VERSION 5.8 ;
BUSBITCHARS "[]" ;
DIVIDERCHAR "/" ;
UNITS
    DATABASE MICRONS 1000 ;
END UNITS

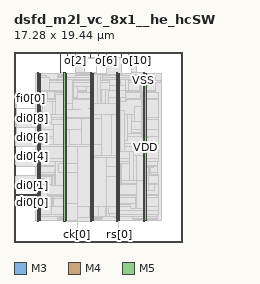
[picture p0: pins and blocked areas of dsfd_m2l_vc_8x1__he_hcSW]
MACRO dsfd_m2l_vc_8x1__he_hcSW
  FOREIGN dsfd_m2l_vc_8x1__he_hcSW 0 0 ;
  CLASS BLOCK ;
  SIZE 17.28 BY 19.44 ;
  PIN ck[0]
    DIRECTION INPUT ;
    USE SIGNAL ;
    PORT
      LAYER M3 ;
        RECT  6.48 0 6.498 0.144 ;
    END
    PORT
      LAYER M3 ;
        RECT  6.48 0.108 6.498 0.173 ;
    END
  END ck[0]
  PIN di0[0]
    DIRECTION INPUT ;
    USE SIGNAL ;
    PORT
      LAYER M4 ;
        RECT  0 4.8 0.192 4.824 ;
    END
    PORT
      LAYER M4 ;
        RECT  0.156 4.8 2.408 4.824 ;
    END
  END di0[0]
  PIN di0[1]
    DIRECTION INPUT ;
    USE SIGNAL ;
    PORT
      LAYER M4 ;
        RECT  0 5.808 0.192 5.832 ;
    END
  END di0[1]
  PIN di0[2]
    DIRECTION INPUT ;
    USE SIGNAL ;
    PORT
      LAYER M4 ;
        RECT  0 6.768 0.192 6.792 ;
    END
  END di0[2]
  PIN di0[3]
    DIRECTION INPUT ;
    USE SIGNAL ;
    PORT
      LAYER M4 ;
        RECT  0 7.776 0.192 7.8 ;
    END
  END di0[3]
  PIN di0[4]
    DIRECTION INPUT ;
    USE SIGNAL ;
    PORT
      LAYER M4 ;
        RECT  0 8.736 0.192 8.76 ;
    END
  END di0[4]
  PIN di0[5]
    DIRECTION INPUT ;
    USE SIGNAL ;
    PORT
      LAYER M4 ;
        RECT  0 9.744 0.192 9.768 ;
    END
  END di0[5]
  PIN di0[6]
    DIRECTION INPUT ;
    USE SIGNAL ;
    PORT
      LAYER M4 ;
        RECT  0 10.704 0.192 10.728 ;
    END
  END di0[6]
  PIN di0[7]
    DIRECTION INPUT ;
    USE SIGNAL ;
    PORT
      LAYER M4 ;
        RECT  0 11.712 0.192 11.736 ;
    END
  END di0[7]
  PIN di0[8]
    DIRECTION INPUT ;
    USE SIGNAL ;
    PORT
      LAYER M4 ;
        RECT  0 12.672 0.192 12.696 ;
    END
  END di0[8]
  PIN di0[9]
    DIRECTION INPUT ;
    USE SIGNAL ;
    PORT
      LAYER M4 ;
        RECT  0 13.68 0.192 13.704 ;
    END
  END di0[9]
  PIN fi0[0]
    DIRECTION INPUT ;
    USE SIGNAL ;
    PORT
      LAYER M4 ;
        RECT  0 14.64 0.192 14.664 ;
    END
  END fi0[0]
  PIN o[0]
    DIRECTION OUTPUT ;
    USE SIGNAL ;
    PORT
      LAYER M3 ;
        RECT  4.716 19.296 4.734 19.44 ;
    END
    PORT
      LAYER M3 ;
        RECT  4.716 17.297 4.734 19.308 ;
    END
  END o[0]
  PIN o[10]
    DIRECTION OUTPUT ;
    USE SIGNAL ;
    PORT
      LAYER M3 ;
        RECT  12.564 19.296 12.582 19.44 ;
    END
    PORT
      LAYER M3 ;
        RECT  12.564 18.845 12.582 19.308 ;
    END
  END o[10]
  PIN o[1]
    DIRECTION OUTPUT ;
    USE SIGNAL ;
    PORT
      LAYER M5 ;
        RECT  5.472 19.248 5.496 19.44 ;
    END
    PORT
      LAYER M5 ;
        RECT  5.472 18.805 5.496 19.28 ;
    END
  END o[1]
  PIN o[2]
    DIRECTION OUTPUT ;
    USE SIGNAL ;
    PORT
      LAYER M3 ;
        RECT  6.264 19.296 6.282 19.44 ;
    END
    PORT
      LAYER M3 ;
        RECT  6.264 18.845 6.282 19.308 ;
    END
  END o[2]
  PIN o[3]
    DIRECTION OUTPUT ;
    USE SIGNAL ;
    PORT
      LAYER M5 ;
        RECT  7.056 19.248 7.08 19.44 ;
    END
    PORT
      LAYER M5 ;
        RECT  7.056 18.805 7.08 19.28 ;
    END
  END o[3]
  PIN o[4]
    DIRECTION OUTPUT ;
    USE SIGNAL ;
    PORT
      LAYER M3 ;
        RECT  7.848 19.296 7.866 19.44 ;
    END
    PORT
      LAYER M3 ;
        RECT  7.848 18.845 7.866 19.308 ;
    END
  END o[4]
  PIN o[5]
    DIRECTION OUTPUT ;
    USE SIGNAL ;
    PORT
      LAYER M5 ;
        RECT  8.64 19.248 8.664 19.44 ;
    END
    PORT
      LAYER M5 ;
        RECT  8.64 18.805 8.664 19.28 ;
    END
  END o[5]
  PIN o[6]
    DIRECTION OUTPUT ;
    USE SIGNAL ;
    PORT
      LAYER M3 ;
        RECT  9.432 19.296 9.45 19.44 ;
    END
    PORT
      LAYER M3 ;
        RECT  9.432 18.914 9.45 19.308 ;
    END
  END o[6]
  PIN o[7]
    DIRECTION OUTPUT ;
    USE SIGNAL ;
    PORT
      LAYER M5 ;
        RECT  10.176 19.248 10.2 19.44 ;
    END
    PORT
      LAYER M5 ;
        RECT  10.176 18.805 10.2 19.28 ;
    END
  END o[7]
  PIN o[8]
    DIRECTION OUTPUT ;
    USE SIGNAL ;
    PORT
      LAYER M3 ;
        RECT  10.98 19.296 10.998 19.44 ;
    END
    PORT
      LAYER M3 ;
        RECT  10.98 18.845 10.998 19.308 ;
    END
  END o[8]
  PIN o[9]
    DIRECTION OUTPUT ;
    USE SIGNAL ;
    PORT
      LAYER M5 ;
        RECT  11.76 19.248 11.784 19.44 ;
    END
    PORT
      LAYER M5 ;
        RECT  11.76 18.805 11.784 19.28 ;
    END
  END o[9]
  PIN rs[0]
    DIRECTION INPUT ;
    USE SIGNAL ;
    PORT
      LAYER M5 ;
        RECT  10.8 0 10.824 0.192 ;
    END
    PORT
      LAYER M5 ;
        RECT  10.8 0.144 10.824 0.227 ;
    END
  END rs[0]
  PIN VDD
    DIRECTION INOUT ;
    USE POWER ;
    PORT
      LAYER M5 ;
        RECT  13.392 2.151 13.512 17.289 ;
        RECT  10.692 2.151 10.812 17.289 ;
        RECT  7.992 2.151 8.112 17.289 ;
        RECT  5.292 2.151 5.412 17.289 ;
        RECT  2.592 2.151 2.712 17.289 ;
    END
  END VDD
  PIN VSS
    DIRECTION INOUT ;
    USE GROUND ;
    PORT
      LAYER M5 ;
        RECT  13.2 2.137 13.32 17.303 ;
        RECT  10.5 2.137 10.62 17.303 ;
        RECT  7.8 2.137 7.92 17.303 ;
        RECT  5.1 2.137 5.22 17.303 ;
        RECT  2.4 2.137 2.52 17.303 ;
    END
  END VSS
  # OT_OBS_CLOSED layer=M5 d_um=1.536 added=14
  OBS
    LAYER RVTN ;
     RECT  2.16 2.16 15.12 2.295 ;
     RECT  2.16 2.565 15.12 2.835 ;
     RECT  2.16 3.105 15.12 3.375 ;
     RECT  2.16 3.645 15.12 3.915 ;
     RECT  2.16 4.185 15.12 4.455 ;
     RECT  2.16 4.725 15.12 4.995 ;
     RECT  2.16 5.265 15.12 5.535 ;
     RECT  2.16 5.805 15.12 6.075 ;
     RECT  2.16 6.345 15.12 6.615 ;
     RECT  2.16 6.885 15.12 7.155 ;
     RECT  2.16 7.425 15.12 7.695 ;
     RECT  2.16 7.965 15.12 8.235 ;
     RECT  2.16 8.505 15.12 8.775 ;
     RECT  2.16 9.045 15.12 9.315 ;
     RECT  2.16 9.585 15.12 9.855 ;
     RECT  2.16 10.125 15.12 10.395 ;
     RECT  2.16 10.665 15.12 10.935 ;
     RECT  2.16 11.205 15.12 11.475 ;
     RECT  2.16 11.745 15.12 12.015 ;
     RECT  2.16 12.285 15.12 12.555 ;
     RECT  2.16 12.825 15.12 13.095 ;
     RECT  2.16 13.365 15.12 13.635 ;
     RECT  2.16 13.905 15.12 14.175 ;
     RECT  2.16 14.445 15.12 14.715 ;
     RECT  2.16 14.985 15.12 15.255 ;
     RECT  2.16 15.525 15.12 15.795 ;
     RECT  2.16 16.065 15.12 16.335 ;
     RECT  2.16 16.605 15.12 16.875 ;
     RECT  2.16 17.145 15.12 17.28 ;
    LAYER RVTP ;
     RECT  2.16 2.295 15.12 2.565 ;
     RECT  2.16 2.835 15.12 3.105 ;
     RECT  2.16 3.375 15.12 3.645 ;
     RECT  2.16 3.915 15.12 4.185 ;
     RECT  2.16 4.455 15.12 4.725 ;
     RECT  2.16 4.995 15.12 5.265 ;
     RECT  2.16 5.535 15.12 5.805 ;
     RECT  2.16 6.075 15.12 6.345 ;
     RECT  2.16 6.615 15.12 6.885 ;
     RECT  2.16 7.155 15.12 7.425 ;
     RECT  2.16 7.695 15.12 7.965 ;
     RECT  2.16 8.235 15.12 8.505 ;
     RECT  2.16 8.775 15.12 9.045 ;
     RECT  2.16 9.315 15.12 9.585 ;
     RECT  2.16 9.855 15.12 10.125 ;
     RECT  2.16 10.395 15.12 10.665 ;
     RECT  2.16 10.935 15.12 11.205 ;
     RECT  2.16 11.475 15.12 11.745 ;
     RECT  2.16 12.015 15.12 12.285 ;
     RECT  2.16 12.555 15.12 12.825 ;
     RECT  2.16 13.095 15.12 13.365 ;
     RECT  2.16 13.635 15.12 13.905 ;
     RECT  2.16 14.175 15.12 14.445 ;
     RECT  2.16 14.715 15.12 14.985 ;
     RECT  2.16 15.255 15.12 15.525 ;
     RECT  2.16 15.795 15.12 16.065 ;
     RECT  2.16 16.335 15.12 16.605 ;
     RECT  2.16 16.875 15.12 17.145 ;
    LAYER M1 ;
     RECT  2.16 2.151 15.12 17.289 ;
    LAYER M2 ;
     RECT  7.843 18.81 8.447 18.828 ;
     RECT  9.427 18.891 10.067 18.909 ;
     RECT  2.16 2.151 15.12 17.289 ;
    LAYER M3 ;
     RECT  10.656 0.187 10.674 2.143 ;
     RECT  13.215 2.143 13.305 2.191 ;
     RECT  12.456 2.191 13.305 2.227 ;
     RECT  5.115 2.143 5.205 2.263 ;
     RECT  12.456 2.227 13.698 2.263 ;
     RECT  14.616 2.191 14.634 2.263 ;
     RECT  7.815 2.143 7.905 2.299 ;
     RECT  4.716 2.263 5.205 2.335 ;
     RECT  6.588 2.293 6.606 2.335 ;
     RECT  7.815 2.299 8.73 2.335 ;
     RECT  4.5 2.335 5.67 2.371 ;
     RECT  6.48 2.335 8.982 2.371 ;
     RECT  12.24 2.263 14.634 2.371 ;
     RECT  2.415 2.143 2.505 2.413 ;
     RECT  10.515 2.143 10.674 2.413 ;
     RECT  10.515 2.413 10.797 2.497 ;
     RECT  4.5 2.371 9.054 2.533 ;
     RECT  4.464 2.533 9.054 2.569 ;
     RECT  10.224 2.497 10.797 2.569 ;
     RECT  4.392 2.569 9.378 2.605 ;
     RECT  2.415 2.413 2.697 2.641 ;
     RECT  4.032 2.605 9.378 2.641 ;
     RECT  10.224 2.569 11.106 2.641 ;
     RECT  12.132 2.371 14.634 2.641 ;
     RECT  2.415 2.641 14.634 2.767 ;
     RECT  2.415 2.767 14.778 3.181 ;
     RECT  2.376 3.181 14.778 3.629 ;
     RECT  2.415 3.629 14.778 4.523 ;
     RECT  2.415 4.523 14.742 4.765 ;
     RECT  2.304 4.765 14.742 4.829 ;
     RECT  2.415 4.829 14.742 5.851 ;
     RECT  2.376 5.851 14.742 5.999 ;
     RECT  2.415 5.999 14.742 6.763 ;
     RECT  2.412 6.763 14.742 6.881 ;
     RECT  2.412 6.881 14.67 7.087 ;
     RECT  2.376 7.087 14.67 7.735 ;
     RECT  2.304 7.735 14.67 7.805 ;
     RECT  2.376 7.805 14.67 8.239 ;
     RECT  2.376 8.239 14.814 8.573 ;
     RECT  2.415 8.573 14.814 9.739 ;
     RECT  2.304 9.739 14.814 10.085 ;
     RECT  2.376 10.085 14.814 10.769 ;
     RECT  2.415 10.769 14.814 11.471 ;
     RECT  2.415 11.471 14.778 12.487 ;
     RECT  2.304 12.487 14.778 12.701 ;
     RECT  2.415 12.701 14.778 14.611 ;
     RECT  2.415 14.611 14.814 14.639 ;
     RECT  2.415 14.639 3.402 14.647 ;
     RECT  4.176 14.639 14.814 15.251 ;
     RECT  2.376 14.647 3.402 15.421 ;
     RECT  4.176 15.251 14.526 15.421 ;
     RECT  2.376 15.421 14.526 15.485 ;
     RECT  2.415 15.485 14.526 16.339 ;
     RECT  2.415 16.339 14.994 16.529 ;
     RECT  2.415 16.529 14.526 16.601 ;
     RECT  2.415 16.601 13.77 16.673 ;
     RECT  2.415 16.673 3.582 16.795 ;
     RECT  2.376 16.795 3.582 16.835 ;
     RECT  4.5 16.673 13.77 16.835 ;
     RECT  14.508 16.601 14.526 16.835 ;
     RECT  4.5 16.835 5.49 16.979 ;
     RECT  2.376 16.835 3.33 17.027 ;
     RECT  4.5 16.979 5.397 17.027 ;
     RECT  2.376 17.027 2.538 17.069 ;
     RECT  3.312 17.027 3.33 17.069 ;
     RECT  6.264 16.835 13.77 17.069 ;
     RECT  4.5 17.027 5.205 17.105 ;
     RECT  11.988 17.069 13.305 17.105 ;
     RECT  6.264 17.069 11.106 17.117 ;
     RECT  9.324 17.117 11.106 17.177 ;
     RECT  6.264 17.117 8.514 17.213 ;
     RECT  2.415 17.069 2.505 17.297 ;
     RECT  4.716 17.105 5.205 17.297 ;
     RECT  6.264 17.213 8.442 17.297 ;
     RECT  12.06 17.105 13.305 17.297 ;
     RECT  6.264 17.297 7.182 18.805 ;
     RECT  8.424 17.297 8.442 18.805 ;
     RECT  6.264 18.805 8.442 18.833 ;
     RECT  6.264 18.833 7.866 18.845 ;
     RECT  9.432 17.177 10.998 18.845 ;
     RECT  12.06 17.297 12.582 18.845 ;
     RECT  9.432 18.845 10.062 18.914 ;
    LAYER M4 ;
     RECT  0.156 13.68 0.275 14.664 ;
     RECT  2.365 3.6 2.408 3.624 ;
     RECT  0.156 5.808 2.408 6.792 ;
     RECT  0.156 7.776 2.408 8.76 ;
     RECT  0.156 9.744 2.408 10.728 ;
     RECT  0.156 11.712 2.408 12.696 ;
     RECT  0.275 13.68 2.408 13.704 ;
     RECT  2.365 15.456 2.408 15.48 ;
     RECT  2.365 16.8 2.408 16.824 ;
     RECT  2.408 2.148 2.512 17.292 ;
     RECT  2.512 2.418 2.704 17.022 ;
     RECT  2.704 9.936 2.819 14.376 ;
     RECT  2.819 12.24 2.917 14.376 ;
     RECT  2.704 15.456 3.593 16.824 ;
     RECT  2.704 3.312 3.805 4.68 ;
     RECT  2.917 12.24 3.805 13.08 ;
     RECT  2.704 5.856 3.841 6.696 ;
     RECT  3.805 12 3.845 13.08 ;
     RECT  3.805 2.832 3.889 4.68 ;
     RECT  3.841 5.808 3.913 6.696 ;
     RECT  3.845 13.056 3.949 13.08 ;
     RECT  2.917 14.352 3.949 14.376 ;
     RECT  2.819 9.936 4.021 10.632 ;
     RECT  3.845 12 4.021 12.024 ;
     RECT  3.889 3.312 4.061 4.68 ;
     RECT  2.704 8.544 4.061 8.568 ;
     RECT  3.913 5.808 4.165 6.84 ;
     RECT  3.949 13.056 4.237 14.376 ;
     RECT  4.165 5.808 4.273 7.464 ;
     RECT  4.061 3.312 5.108 3.336 ;
     RECT  4.061 4.464 5.108 4.68 ;
     RECT  4.273 5.808 5.108 8.232 ;
     RECT  4.021 9.936 5.108 12.024 ;
     RECT  4.237 13.056 5.108 15.048 ;
     RECT  5.108 2.148 5.212 17.292 ;
     RECT  5.212 2.418 5.404 17.022 ;
     RECT  5.404 13.584 6.035 16.632 ;
     RECT  6.035 14.832 6.049 16.632 ;
     RECT  5.404 3.984 6.275 8.808 ;
     RECT  6.275 3.984 6.316 5.832 ;
     RECT  6.275 6.816 6.469 8.808 ;
     RECT  5.404 10.176 6.469 12.312 ;
     RECT  6.049 14.832 6.473 15.864 ;
     RECT  6.428 0.144 6.515 0.168 ;
     RECT  5.404 2.544 6.577 2.568 ;
     RECT  6.469 6.816 6.581 12.312 ;
     RECT  6.577 2.304 6.649 2.568 ;
     RECT  6.316 3.984 6.649 4.584 ;
     RECT  6.035 13.584 6.761 13.608 ;
     RECT  6.581 7.2 6.829 12.312 ;
     RECT  5.461 18.816 7.193 18.84 ;
     RECT  6.316 5.76 7.261 5.832 ;
     RECT  6.649 2.304 7.369 4.584 ;
     RECT  7.261 5.76 7.369 6.216 ;
     RECT  6.473 15.504 7.441 15.864 ;
     RECT  7.369 2.304 7.808 6.216 ;
     RECT  6.829 7.2 7.808 12.648 ;
     RECT  7.657 13.632 7.808 13.656 ;
     RECT  7.441 15.312 7.808 15.864 ;
     RECT  7.477 17.088 7.808 17.112 ;
     RECT  7.808 2.148 7.912 17.292 ;
     RECT  7.912 2.304 8.021 17.112 ;
     RECT  8.021 2.418 8.104 17.112 ;
     RECT  8.104 8.544 8.561 17.112 ;
     RECT  8.104 2.64 8.669 7.368 ;
     RECT  8.561 9.792 8.849 17.112 ;
     RECT  8.849 9.792 8.963 15.576 ;
     RECT  8.849 16.56 9.065 17.112 ;
     RECT  8.963 11.232 9.317 15.576 ;
     RECT  8.669 2.64 9.349 7.32 ;
     RECT  9.317 12.576 9.353 15.576 ;
     RECT  8.561 8.544 9.421 8.808 ;
     RECT  9.349 2.592 9.461 7.32 ;
     RECT  9.421 8.448 9.884 8.808 ;
     RECT  8.963 9.792 9.884 10.2 ;
     RECT  9.065 16.56 10.141 16.584 ;
     RECT  9.884 8.448 10.249 10.2 ;
     RECT  9.317 11.232 10.249 11.4 ;
     RECT  9.461 5.232 10.309 7.32 ;
     RECT  10.249 8.448 10.309 11.4 ;
     RECT  10.141 16.56 10.309 16.632 ;
     RECT  9.353 12.768 10.429 15.576 ;
     RECT  10.309 16.56 10.429 16.824 ;
     RECT  8.629 18.816 10.469 18.84 ;
     RECT  9.461 2.592 10.508 4.248 ;
     RECT  10.309 5.232 10.508 11.4 ;
     RECT  10.429 12.768 10.508 16.824 ;
     RECT  10.508 2.148 10.612 17.292 ;
     RECT  10.612 2.418 10.804 17.022 ;
     RECT  10.645 0.192 10.835 0.216 ;
     RECT  10.804 9.216 10.901 16.632 ;
     RECT  10.804 5.76 10.937 7.992 ;
     RECT  10.937 6 11.009 7.992 ;
     RECT  10.901 9.216 11.333 13.416 ;
     RECT  10.901 14.4 11.459 16.632 ;
     RECT  11.459 14.4 11.513 14.472 ;
     RECT  11.333 10.368 11.657 13.08 ;
     RECT  11.459 15.456 11.729 16.632 ;
     RECT  11.009 6.288 11.833 7.992 ;
     RECT  11.333 9.216 11.833 9.24 ;
     RECT  10.804 3.888 11.941 3.96 ;
     RECT  11.657 11.136 12.053 13.08 ;
     RECT  11.749 18.816 12.089 18.84 ;
     RECT  11.833 6.288 12.197 9.24 ;
     RECT  12.053 12.288 12.301 13.08 ;
     RECT  11.941 3.408 12.476 3.96 ;
     RECT  12.197 6.288 12.517 8.856 ;
     RECT  11.729 15.456 12.841 15.48 ;
     RECT  11.729 16.56 12.841 16.632 ;
     RECT  12.841 15.456 12.913 16.632 ;
     RECT  12.913 14.928 12.985 16.632 ;
     RECT  12.053 11.136 13.052 11.16 ;
     RECT  12.301 12.288 13.052 13.848 ;
     RECT  13.052 11.136 13.093 13.848 ;
     RECT  12.985 14.832 13.093 16.632 ;
     RECT  12.517 2.208 13.208 2.232 ;
     RECT  12.476 3.408 13.208 4.536 ;
     RECT  12.517 5.616 13.208 8.856 ;
     RECT  13.093 10.704 13.208 16.632 ;
     RECT  13.208 2.148 13.312 17.292 ;
     RECT  13.312 2.418 13.504 17.022 ;
     RECT  13.504 3.696 13.565 3.72 ;
     RECT  13.504 10.704 13.742 10.728 ;
     RECT  13.504 5.28 13.745 7.656 ;
     RECT  13.504 9.216 13.781 9.24 ;
     RECT  13.745 6.864 13.907 7.656 ;
     RECT  13.907 7.008 13.961 7.656 ;
     RECT  13.504 16.032 14.069 16.056 ;
     RECT  13.961 7.632 14.285 7.656 ;
     RECT  13.745 5.28 14.357 5.88 ;
     RECT  14.357 5.856 14.465 5.88 ;
     RECT  13.504 14.688 14.753 14.712 ;
    LAYER M5 ;
     RECT  2.4 2.137 2.52 2.151 ;
     RECT  5.1 2.137 5.22 2.151 ;
     RECT  7.8 2.137 7.92 2.151 ;
     RECT  10.5 2.137 10.62 2.151 ;
     RECT  13.2 2.137 13.32 2.151 ;
     RECT  7.8 2.151 8.112 2.533 ;
     RECT  10.5 2.151 10.812 2.581 ;
     RECT  9.792 2.581 10.812 2.869 ;
     RECT  13.2 2.151 13.512 3.397 ;
     RECT  2.4 2.151 2.712 3.589 ;
     RECT  3.84 2.821 3.864 3.589 ;
     RECT  9.696 2.869 10.812 3.589 ;
     RECT  2.4 3.589 3.864 3.635 ;
     RECT  7.68 2.533 8.112 3.635 ;
     RECT  5.1 2.151 5.412 3.973 ;
     RECT  6.48 0.133 6.504 3.973 ;
     RECT  2.4 3.635 2.952 4.645 ;
     RECT  2.4 4.645 3.432 5.891 ;
     RECT  12.528 3.397 13.512 6.323 ;
     RECT  2.4 5.891 3.24 6.515 ;
     RECT  9.456 3.589 10.812 6.661 ;
     RECT  13.2 6.323 13.512 6.853 ;
     RECT  13.2 6.853 13.896 7.043 ;
     RECT  5.1 3.973 6.504 7.093 ;
     RECT  9.456 6.661 10.92 7.763 ;
     RECT  4.56 7.093 6.504 8.003 ;
     RECT  7.8 3.635 8.112 8.677 ;
     RECT  9.456 7.763 10.812 8.677 ;
     RECT  7.8 8.677 10.812 8.819 ;
     RECT  5.1 8.003 6.504 9.731 ;
     RECT  7.8 8.819 8.952 9.925 ;
     RECT  13.2 7.043 13.512 10.693 ;
     RECT  2.4 6.515 2.712 11.365 ;
     RECT  5.1 9.731 5.688 11.555 ;
     RECT  2.4 11.365 2.808 12.275 ;
     RECT  6.912 9.925 8.952 12.611 ;
     RECT  7.008 12.611 8.952 12.659 ;
     RECT  7.8 12.659 8.952 13.045 ;
     RECT  9.936 8.819 10.812 13.045 ;
     RECT  2.4 12.275 2.712 13.429 ;
     RECT  7.8 13.045 10.812 14.147 ;
     RECT  5.1 11.555 5.412 14.197 ;
     RECT  2.4 13.429 2.904 14.387 ;
     RECT  0.24 10.357 0.264 14.675 ;
     RECT  9.696 14.147 10.812 14.773 ;
     RECT  13.104 10.693 13.512 15.443 ;
     RECT  9.696 14.773 11.448 15.491 ;
     RECT  9.744 15.491 11.448 16.019 ;
     RECT  9.744 16.019 10.812 16.595 ;
     RECT  5.1 14.197 6.024 16.643 ;
     RECT  10.32 16.595 10.812 16.835 ;
     RECT  2.4 14.387 2.712 17.289 ;
     RECT  5.1 16.643 5.412 17.289 ;
     RECT  7.8 14.147 8.112 17.289 ;
     RECT  10.5 16.835 10.812 17.289 ;
     RECT  13.2 15.443 13.512 17.289 ;
     RECT  2.4 17.289 2.52 17.303 ;
     RECT  5.1 17.289 5.22 17.303 ;
     RECT  7.8 17.289 7.92 17.303 ;
     RECT  10.5 17.289 10.62 17.303 ;
     RECT  13.2 17.289 13.32 17.303 ;
     RECT  5.22 2.137 6.48 2.151 ;
     RECT  6.504 2.137 7.8 2.533 ;
     RECT  5.412 2.151 6.48 3.973 ;
     RECT  6.504 2.533 7.68 3.635 ;
     RECT  2.712 2.821 3.84 3.589 ;
     RECT  3.864 2.821 5.1 3.635 ;
     RECT  8.112 3.589 9.456 8.677 ;
     RECT  2.952 3.635 3.432 4.645 ;
     RECT  6.504 3.635 7.8 9.731 ;
     RECT  8.952 8.819 9.936 13.045 ;
     RECT  5.688 9.731 7.8 9.925 ;
     RECT  5.688 9.925 6.912 11.555 ;
     RECT  5.412 11.555 6.912 12.611 ;
     RECT  2.712 12.275 2.808 13.429 ;
  END
END dsfd_m2l_vc_8x1__he_hcSW
END LIBRARY
